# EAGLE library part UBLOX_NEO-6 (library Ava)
UBLOX NEO-6 GPS MODULE Author Anthony Stirk / http://ava.upuaut.net http://www.u-blox.com/images/downloads/Product_Docs/LEA-6_NEO-6_MAX_HardwareIntegrationManual_%28GPS.G6-HW-09007%29.pdf http://www.u-blox.com/images/downloads/Product_Docs/NEO-6_DataSheet_%28GPS.G6-HW-09005%29.pdf

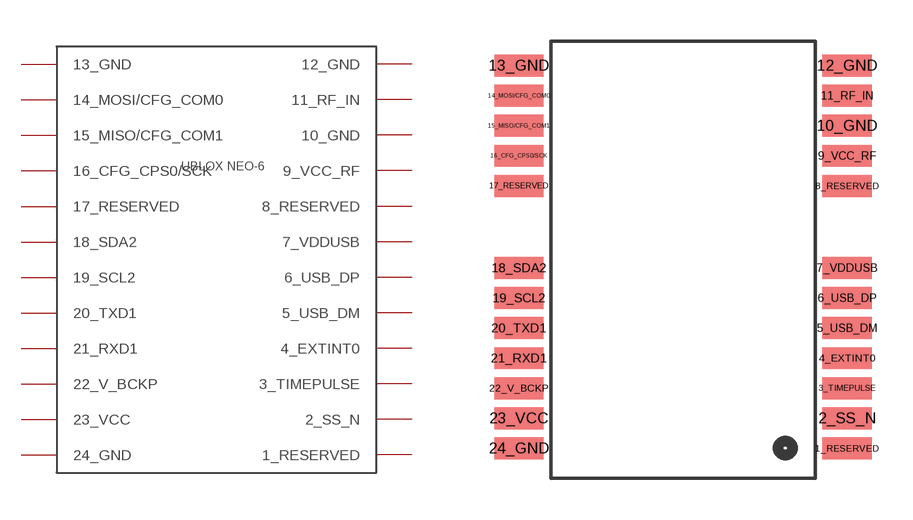
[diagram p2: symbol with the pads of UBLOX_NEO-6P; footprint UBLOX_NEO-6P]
Designator prefix -

## UBLOX_NEO-6  [UBLOX_NEO-6P]
1_RESERVED  1_RESERVED
2_SS_N  2_SS_N
3_TIMEPULSE  3_TIMEPULSE
4_EXTINT0  4_EXTINT0
5_USB_DM  5_USB_DM
6_USB_DP  6_USB_DP
7_VDDUSB  7_VDDUSB
8_RESERVED  8_RESERVED
9_VCC_RF  9_VCC_RF
10_GND  10_GND
11_RF_IN  11_RF_IN
12_GND  12_GND
13_GND  13_GND
14_MOSI/CFG_COM0  14_MOSI/CFG_COM0
15_MISO/CFG_COM1  15_MISO/CFG_COM1
16_CFG_CPS0/SCK  16_CFG_CPS0/SCK
17_RESERVED  17_RESERVED
18_SDA2  18_SDA2
19_SCL2  19_SCL2
20_TXD1  20_TXD1
21_RXD1  21_RXD1
22_V_BCKP  22_V_BCKP
23_VCC  23_VCC
24_GND  24_GND

## Footprint UBLOX_NEO-6P (pad centres in mm)
NEO-6 Series - u-blox 6 NEO Series GALILEO-Ready GPS Modules The NEO-6 module series brings the high performance, 50-channel u-blox 6 positioning engine, to the miniature NEO form factor. The u-blox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
smd 1.8 x 0.8: 1_RESERVED 6.4,-7.4; 2_SS_N 6.4,-6.3; 3_TIMEPULSE 6.4,-5.2; 4_EXTINT0 6.4,-4.1; 5_USB_DM 6.4,-3; 6_USB_DP 6.4,-1.9; 7_VDDUSB 6.4,-0.8; 8_RESERVED 6.4,2.2; 9_VCC_RF 6.4,3.3; 10_GND 6.4,4.4; 11_RF_IN 6.4,5.5; 12_GND 6.4,6.6; 13_GND -5.6,6.6; 14_MOSI/CFG_COM0 -5.6,5.5; 15_MISO/CFG_COM1 -5.6,4.4; 16_CFG_CPS0/SCK -5.6,3.3; 17_RESERVED -5.6,2.2; 18_SDA2 -5.6,-0.8; 19_SCL2 -5.6,-1.9; 20_TXD1 -5.6,-3; 21_RXD1 -5.6,-4.1; 22_V_BCKP -5.6,-5.2; 23_VCC -5.6,-6.3; 24_GND -5.6,-7.4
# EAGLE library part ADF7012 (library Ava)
ADF7012 Multichannel ISM Band FSK/GFSK/OOK/GOOK/ASK Transmitter http://www.analog.com/static/imported-files/data_sheets/ADF7012.pdf

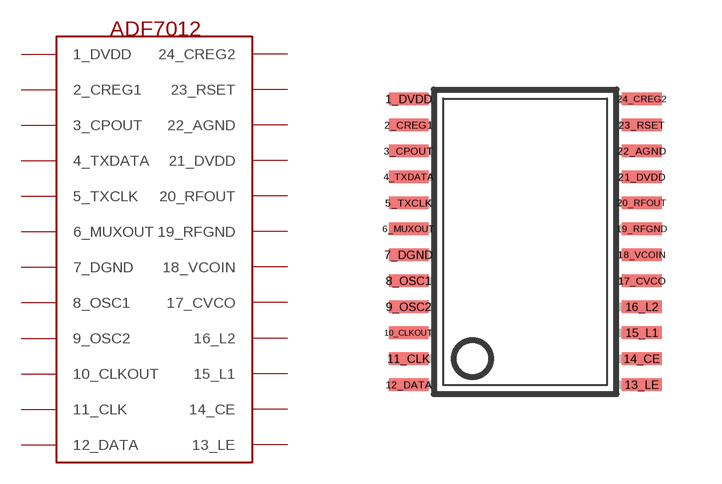
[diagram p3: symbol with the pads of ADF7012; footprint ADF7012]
Designator prefix -

## ADF7012  [ADF7012]
1_DVDD  1_DVDD
2_CREG1  2_CREG1
3_CPOUT  3_CPOUT
4_TXDATA  4_TXDATA
5_TXCLK  5_TXCLK
6_MUXOUT  6_MUXOUT
7_DGND  7_DGND
8_OSC1  8_OSC1
9_OSC2  9_OSC2
10_CLKOUT  10_CLKOUT
11_CLK  11_CLK
12_DATA  12_DATA
13_LE  13_LE
14_CE  14_CE
15_L1  15_L1
16_L2  16_L2
17_CVCO  17_CVCO
18_VCOIN  18_VCOIN
19_RFGND  19_RFGND
20_RFOUT  20_RFOUT
21_DVDD  21_DVDD
22_AGND  22_AGND
23_RSET  23_RSET
24_CREG2  24_CREG2

## Footprint ADF7012 (pad centres in mm)
ADF7012 Multichannel ISM Band FSK/GFSK/OOK/GOOK/ASK Transmitter http://www.analog.com/static/imported-files/data_sheets/ADF7012.pdf
smd 0.991 x 0.305: 1_DVDD -5.458,8.655; 2_CREG1 -5.458,8.005; 3_CPOUT -5.458,7.355; 4_TXDATA -5.458,6.705; 5_TXCLK -5.458,6.055; 6_MUXOUT -5.458,5.405; 7_DGND -5.458,4.755; 8_OSC1 -5.458,4.105; 9_OSC2 -5.458,3.455; 10_CLKOUT -5.458,2.805; 11_CLK -5.458,2.155; 12_DATA -5.458,1.505; 13_LE 0.378,1.505; 14_CE 0.378,2.155; 15_L1 0.378,2.805; 16_L2 0.378,3.455; 17_CVCO 0.378,4.105; 18_VCOIN 0.378,4.755; 19_RFGND 0.378,5.405; 20_RFOUT 0.378,6.055; 21_DVDD 0.378,6.705; 22_AGND 0.378,7.355; 23_RSET 0.378,8.005; 24_CREG2 0.378,8.655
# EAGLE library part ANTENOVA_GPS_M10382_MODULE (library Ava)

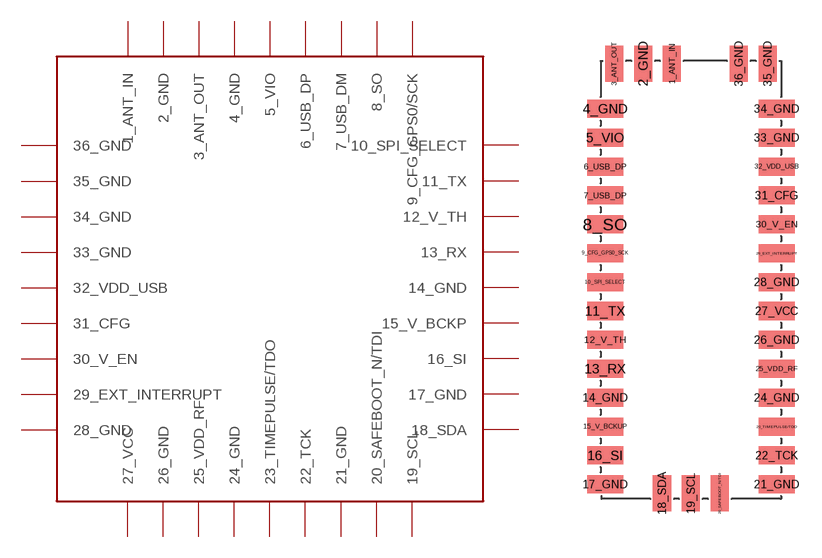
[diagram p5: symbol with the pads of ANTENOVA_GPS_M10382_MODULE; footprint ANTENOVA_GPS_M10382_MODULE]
Designator prefix -

## ANTENOVA_GPS_M10382_MODULE  [ANTENOVA_GPS_M10382_MODULE]
1_ANT_IN  1_ANT_IN
2_GND  2_GND
3_ANT_OUT  3_ANT_OUT
4_GND  4_GND
5_VIO  5_VIO
6_USB_DP  6_USB_DP
7_USB_DP  7_USB_DM
8_SO  8_SO
9_CFG_GPS0_SCK  9_CFG_GPS0/SCK
10_SPI_SELECT  10_SPI_SELECT
11_TX  11_TX
12_V_TH  12_V_TH
13_RX  13_RX
14_GND  14_GND
15_V_BCKUP  15_V_BCKP
16_SI  16_SI
17_GND  17_GND
18_SDA  18_SDA
19_SCL  19_SCL
20_SAFEBOOT_N/TDI  20_SAFEBOOT_N/TDI
21_GND  21_GND
22_TCK  22_TCK
23_TIMEPULSE/TDO  23_TIMEPULSE/TDO
24_GND  24_GND
25_VDD_RF  25_VDD_RF
26_GND  26_GND
27_VCC  27_VCC
28_GND  28_GND
29_EXT_INTERRUPT  29_EXT_INTERRUPT
30_V_EN  30_V_EN
31_CFG  31_CFG
32_VDD_USB  32_VDD_USB
33_GND  33_GND
34_GND  34_GND
35_GND  35_GND
36_GND  36_GND

## Footprint ANTENOVA_GPS_M10382_MODULE (pad centres in mm)
GPS RADIONOVA M10382 RF Antenna Module (SMD) Low profile SMD mount u-blox 6 based GPS radio antenna module suitable for L1-band and A-GPS systems. Dimensions: 24.2 x 9.9 x 3.9mm Frequency: 1575 MHz
smd 1 x 2: 1_ANT_IN -1.38,12.43; 2_GND -2.98,12.43; 3_ANT_OUT -4.58,12.43; 18_SDA -1.93,-11.37; 19_SCL -0.33,-11.37; 20_SAFEBOOT_N/TDI 1.27,-11.37; 35_GND 3.92,12.43; 36_GND 2.32,12.43
smd 2 x 1: 4_GND -5.08,9.93; 5_VIO -5.08,8.33; 6_USB_DP -5.08,6.73; 7_USB_DP -5.08,5.13; 8_SO -5.08,3.53; 9_CFG_GPS0_SCK -5.08,1.93; 10_SPI_SELECT -5.08,0.33; 11_TX -5.08,-1.27; 12_V_TH -5.08,-2.87; 13_RX -5.08,-4.47; 14_GND -5.08,-6.07; 15_V_BCKUP -5.08,-7.67; 16_SI -5.08,-9.27; 17_GND -5.08,-10.87; 21_GND 4.42,-10.87; 22_TCK 4.42,-9.27; 23_TIMEPULSE/TDO 4.42,-7.67; 24_GND 4.42,-6.07; 25_VDD_RF 4.42,-4.47; 26_GND 4.42,-2.87; 27_VCC 4.42,-1.27; 28_GND 4.42,0.33; 29_EXT_INTERRUPT 4.42,1.93; 30_V_EN 4.42,3.53; 31_CFG 4.42,5.13; 32_VDD_USB 4.42,6.73; 33_GND 4.42,8.33; 34_GND 4.42,9.93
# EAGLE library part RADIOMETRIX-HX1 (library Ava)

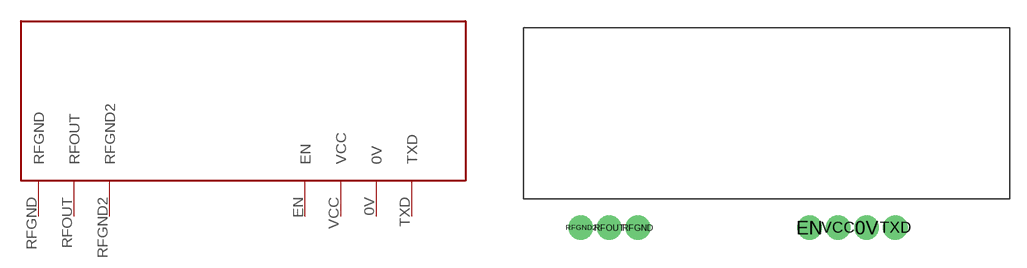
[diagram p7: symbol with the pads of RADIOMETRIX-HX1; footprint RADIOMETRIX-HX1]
Designator prefix -

## RADIOMETRIX-HX1  [RADIOMETRIX-HX1]
0V  0V
EN  EN
RFGND  RFGND
RFGND2  RFGND2
RFOUT  RFOUT
TXD  TXD
VCC  VCC

## Footprint RADIOMETRIX-HX1 (pad centres in mm)
drill 0.7 pad 2.184: 0V 8.89,-10.16; EN 3.81,-10.16; RFGND -11.43,-10.16; RFGND2 -16.51,-10.16; RFOUT -13.97,-10.16; TXD 11.43,-10.16; VCC 6.35,-10.16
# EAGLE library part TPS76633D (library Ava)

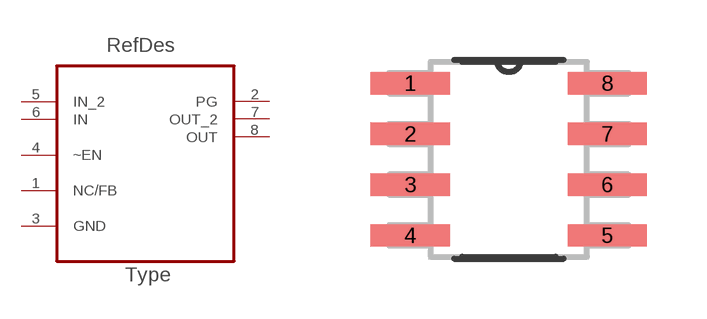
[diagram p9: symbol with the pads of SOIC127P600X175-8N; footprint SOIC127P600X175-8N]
Designator prefix U

## TPS76633D (DESCRIPTION: ULTRALOW QUIESCENT CURRENT 250-mA LOW DROPOUT VOLTAGE REGULATORS; MPN: TPS76633D; OC_FARNELL: 8461422; OC_NEWARK: 77C1060; PACKAGE: SOIC-8; SUPPLIER: Texas Instruments)  [SOIC127P600X175-8N]
1  NC/FB  nc
2  PG  out
3  GND  pas
4  ~EN  in
5  IN_2  in
6  IN  in
7  OUT_2  out
8  OUT  out

## Footprint SOIC127P600X175-8N (pad centres in mm)
smd 1.981 x 0.559: 1 -2.464,1.905; 2 -2.464,0.635; 3 -2.464,-0.635; 4 -2.464,-1.905; 5 2.464,-1.905; 6 2.464,-0.635; 7 2.464,0.635; 8 2.464,1.905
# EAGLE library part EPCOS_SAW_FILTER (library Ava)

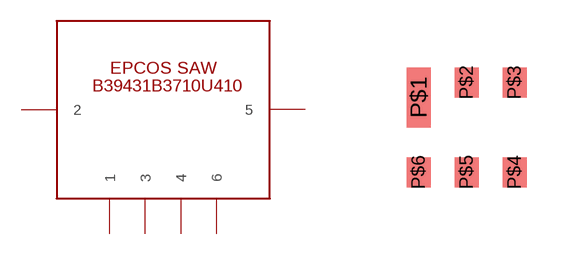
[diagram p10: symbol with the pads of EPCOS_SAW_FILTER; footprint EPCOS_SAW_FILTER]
Designator prefix -

## EPCOS_SAW_FILTER  [EPCOS_SAW_FILTER]
P$1  1
P$2  2
P$3  3
P$4  4
P$5  5
P$6  6

## Footprint EPCOS_SAW_FILTER (pad centres in mm)
smd 0.6 x 1.5: P$1 -1.2,0.75
smd 0.6 x 0.75: P$2 0,1.125; P$3 1.2,1.125; P$4 1.2,-1.125; P$5 0,-1.125; P$6 -1.2,-1.125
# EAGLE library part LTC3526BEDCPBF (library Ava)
Low Dropout Linear Regulators

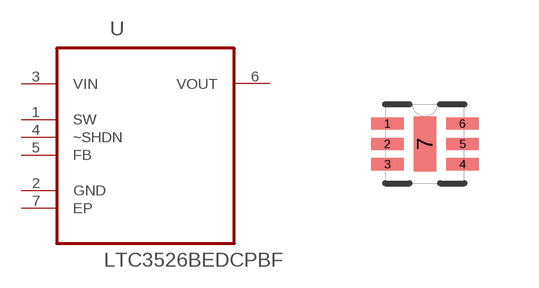
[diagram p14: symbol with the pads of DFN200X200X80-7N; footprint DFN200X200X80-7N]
Designator prefix U

## LTC3526BEDCPBF (MPN: LTC3526BEDC#PBF; OC_FARNELL: 1858699; OC_NEWARK: 61R9521; PACKAGE: DFN-6; SUPPLIER: Linear Technology)  [DFN200X200X80-7N]
1  SW  pas
2  GND  pas
3  VIN  pwr
4  ~SHDN  in
5  FB  in
6  VOUT  out
7  EP  pas

## Footprint DFN200X200X80-7N (pad centres in mm)
smd 0.813 x 0.305: 1 -0.94,0.508; 2 -0.94,0; 3 -0.94,-0.508; 4 0.94,-0.508; 5 0.94,0; 6 0.94,0.508
smd 0.559 x 1.372: 7 0,0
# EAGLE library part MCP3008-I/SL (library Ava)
10BIT ADC, 8 CH, SPI, SMD

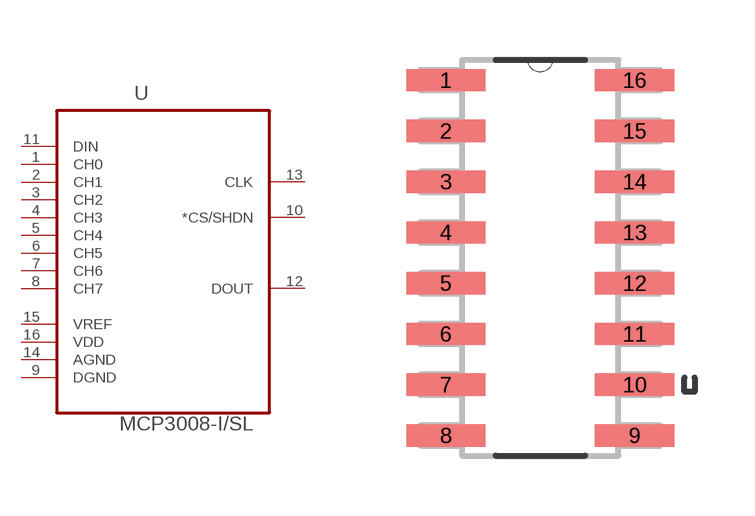
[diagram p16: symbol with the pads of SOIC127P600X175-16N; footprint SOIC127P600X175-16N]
Designator prefix U

## MCP3008-I/SL (MPN: MCP3008-I/SL; OC_FARNELL: 1292241; OC_NEWARK: 19C7201; PACKAGE: SOIC16; SUPPLIER: Microchip)  [SOIC127P600X175-16N]
1  CH0  in
2  CH1  in
3  CH2  in
4  CH3  in
5  CH4  in
6  CH5  in
7  CH6  in
8  CH7  in
9  DGND  pas
10  *CS/SHDN  in
11  DIN  in
12  DOUT  out
13  CLK  in
14  AGND  pas
15  VREF  in
16  VDD  pwr

## Footprint SOIC127P600X175-16N (pad centres in mm)
smd 1.981 x 0.559: 1 -2.362,4.445; 2 -2.362,3.175; 3 -2.362,1.905; 4 -2.362,0.635; 5 -2.362,-0.635; 6 -2.362,-1.905; 7 -2.362,-3.175; 8 -2.362,-4.445; 9 2.362,-4.445; 10 2.362,-3.175; 11 2.362,-1.905; 12 2.362,-0.635; 13 2.362,0.635; 14 2.362,1.905; 15 2.362,3.175; 16 2.362,4.445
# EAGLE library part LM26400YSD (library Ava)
Wide Input Range Buck Regulator

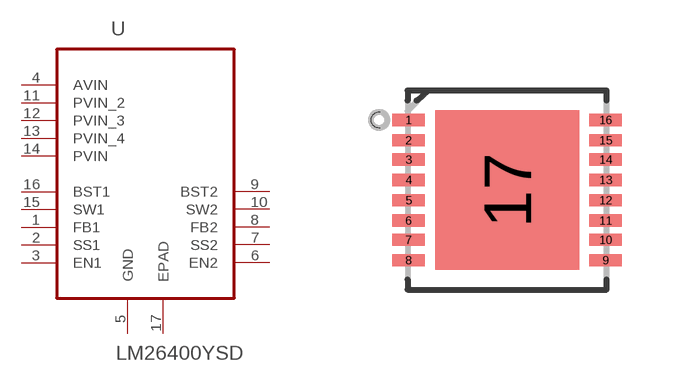
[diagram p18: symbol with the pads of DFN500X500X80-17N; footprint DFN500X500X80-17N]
Designator prefix U

## LM26400YSD (MPN: LM26400YSD; OC_FARNELL: 1333957; OC_NEWARK: 34M6729; PACKAGE: DFN-16; SUPPLIER: National Semiconductors)  [DFN500X500X80-17N]
1  FB1  in
2  SS1  in
3  EN1  in
4  AVIN  pwr
5  GND  pas
6  EN2  in
7  SS2  in
8  FB2  in
9  BST2  in
10  SW2  out
11  PVIN_2  pwr
12  PVIN_3  pwr
13  PVIN_4  pwr
14  PVIN  pwr
15  SW1  out
16  BST1  in
17  EPAD  pas

## Footprint DFN500X500X80-17N (pad centres in mm)
smd 0.813 x 0.305: 1 -2.464,1.753; 2 -2.464,1.245; 3 -2.464,0.762; 4 -2.464,0.254; 5 -2.464,-0.254; 6 -2.464,-0.762; 7 -2.464,-1.245; 8 -2.464,-1.753; 9 2.464,-1.753; 10 2.464,-1.245; 11 2.464,-0.762; 12 2.464,-0.254; 13 2.464,0.254; 14 2.464,0.762; 15 2.464,1.245; 16 2.464,1.753
smd 3.607 x 3.988: 17 0,0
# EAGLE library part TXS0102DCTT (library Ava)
BIDIRECTIONAL VOLTAGE-LEVEL TRANSLATOR

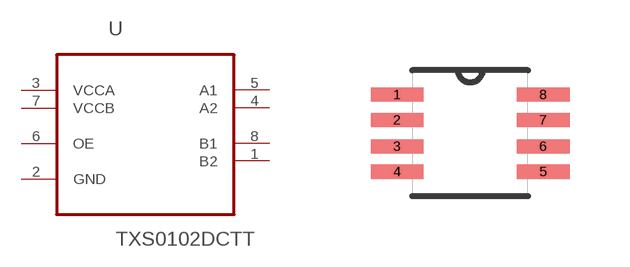
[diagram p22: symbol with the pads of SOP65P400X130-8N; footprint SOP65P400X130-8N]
Designator prefix U

## TXS0102DCTT (MPN: TXS0102DCTT; OC_FARNELL: 1567203; OC_NEWARK: 48M1002; PACKAGE: SSOP-8; SUPPLIER: Texas Instruments)  [SOP65P400X130-8N]
1  B2
2  GND  pas
3  VCCA  pwr
4  A2
5  A1
6  OE  in
7  VCCB  pwr
8  B1

## Footprint SOP65P400X130-8N (pad centres in mm)
smd 1.321 x 0.356: 1 -1.829,0.965; 2 -1.829,0.33; 3 -1.829,-0.33; 4 -1.829,-0.965; 5 1.829,-0.965; 6 1.829,-0.33; 7 1.829,0.33; 8 1.829,0.965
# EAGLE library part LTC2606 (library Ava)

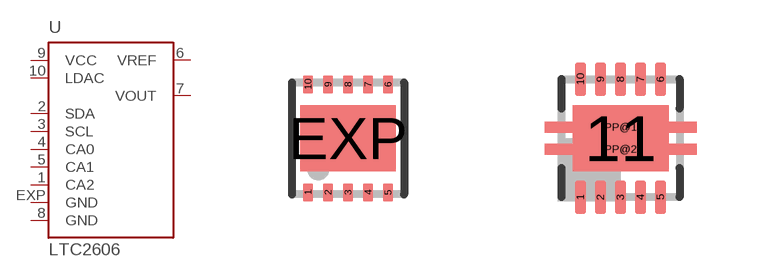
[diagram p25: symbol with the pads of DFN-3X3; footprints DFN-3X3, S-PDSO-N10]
Designator prefix -

## LTC2606  [DFN-3X3]
1  CA2  in
2  SDA  in
3  SCL  out
4  CA0  in
5  CA1  in
6  VREF  in
7  VOUT  in
8  GND  pwr
9  VCC  pwr
10  LDAC  in
EXP  GND  pwr

## LTC2606LARGERPADS  [S-PDSO-N10]
1  CA2  in
2  SDA  in
3  SCL  out
4  CA0  in
5  CA1  in
6  VREF  in
7  VOUT  in
8  GND  pwr
9  VCC  pwr
10  LDAC  in
11  GND  pwr
PP@1  GND  pwr
PP@2  GND  pwr

## Footprint DFN-3X3 (pad centres in mm)
smd 0.25 x 0.45: 1 -1,-1.35; 2 -0.5,-1.35; 3 0,-1.35; 4 0.5,-1.35; 5 1,-1.35; 6 1,1.35; 7 0.5,1.35; 8 0,1.35; 9 -0.5,1.35; 10 -1,1.35
smd 2.38 x 1.65: EXP 0,0

## Footprint S-PDSO-N10 (pad centres in mm)
smd 0.28 x 0.85: 1 -1,-1.475; 2 -0.5,-1.475; 3 0,-1.475; 4 0.5,-1.475; 5 1,-1.475; 6 1,1.475; 7 0.5,1.475; 8 0,1.475; 9 -0.5,1.475; 10 -1,1.475
smd 2.4 x 1.65: 11 0,0
smd 3.8 x 0.28: PP@1 0,0.275; PP@2 0,-0.275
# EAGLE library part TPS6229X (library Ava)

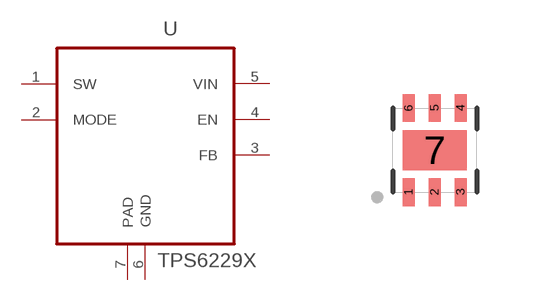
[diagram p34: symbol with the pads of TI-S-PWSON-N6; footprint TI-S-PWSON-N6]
Designator prefix -

## TPS6229X  [TI-S-PWSON-N6]
1  SW  pwr
2  MODE  pas
3  FB  in
4  EN  in
5  VIN  out
6  GND  pas
7  PAD  pas

## Footprint TI-S-PWSON-N6 (pad centres in mm)
smd 0.3 x 0.7: 1 -0.65,-1.05; 2 0,-1.05; 3 0.65,-1.05; 4 0.65,1.05; 5 0,1.05; 6 -0.65,1.05
smd 1.6 x 1: 7 0,0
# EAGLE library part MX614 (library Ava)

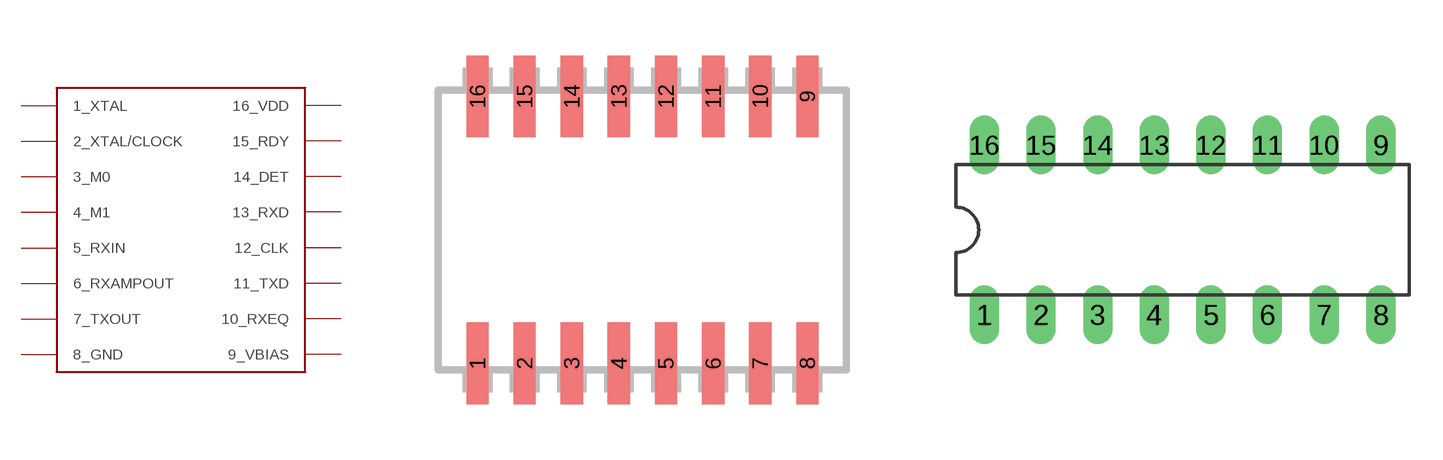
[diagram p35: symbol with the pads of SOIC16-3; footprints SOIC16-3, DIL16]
Designator prefix -

## MX614  [SOIC16-3]
1  1_XTAL  pwr
2  2_XTAL/CLOCK
3  3_M0
4  4_M1
5  5_RXIN
6  6_RXAMPOUT
7  7_TXOUT  pwr
8  8_GND  pwr
9  9_VBIAS  pwr
10  10_RXEQ  pwr
11  11_TXD
12  12_CLK  pwr
13  13_RXD
14  14_DET
15  15_RDY
16  16_VDD

## MX614DIL16  [DIL16]
Pads as for SOIC16-3

## Footprint SOIC16-3 (pad centres in mm)
smd 0.6 x 2.2: 1 -4.445,-3.6; 2 -3.175,-3.6; 3 -1.905,-3.6; 4 -0.635,-3.6; 5 0.635,-3.6; 6 1.905,-3.6; 7 3.175,-3.6; 8 4.445,-3.6; 9 4.445,3.6; 10 3.175,3.6; 11 1.905,3.6; 12 0.635,3.6; 13 -0.635,3.6; 14 -1.905,3.6; 15 -3.175,3.6; 16 -4.445,3.6

## Footprint DIL16 (pad centres in mm)
drill 0.813 long: 1 -8.89,-3.81; 2 -6.35,-3.81; 3 -3.81,-3.81; 4 -1.27,-3.81; 5 1.27,-3.81; 6 3.81,-3.81; 7 6.35,-3.81; 8 8.89,-3.81; 9 8.89,3.81; 10 6.35,3.81; 11 3.81,3.81; 12 1.27,3.81; 13 -1.27,3.81; 14 -3.81,3.81; 15 -6.35,3.81; 16 -8.89,3.81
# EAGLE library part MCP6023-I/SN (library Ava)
IC OPAMP 2.5V R-R I/O

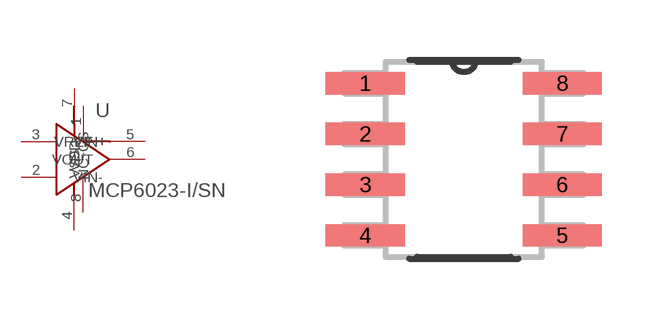
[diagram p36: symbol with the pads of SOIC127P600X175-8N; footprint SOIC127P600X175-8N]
Designator prefix U

## MCP6023-I/SN (MPN: MCP6023-I/SN; OC_FARNELL: 1629353; OC_NEWARK: 92C2412; PACKAGE: 8 SOIC; SUPPLIER: Microchip)  [SOIC127P600X175-8N]
1  NC  nc
2  VIN-  in
3  VIN+  in
4  VSS  pas
5  VREF  out
6  VOUT  out
7  VDD  pwr
8  ~CS  out

## Footprint SOIC127P600X175-8N (pad centres in mm)
smd 1.981 x 0.559: 1 -2.464,1.905; 2 -2.464,0.635; 3 -2.464,-0.635; 4 -2.464,-1.905; 5 2.464,-1.905; 6 2.464,-0.635; 7 2.464,0.635; 8 2.464,1.905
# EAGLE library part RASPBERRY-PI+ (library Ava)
Samtec SSW-120-01-T-D

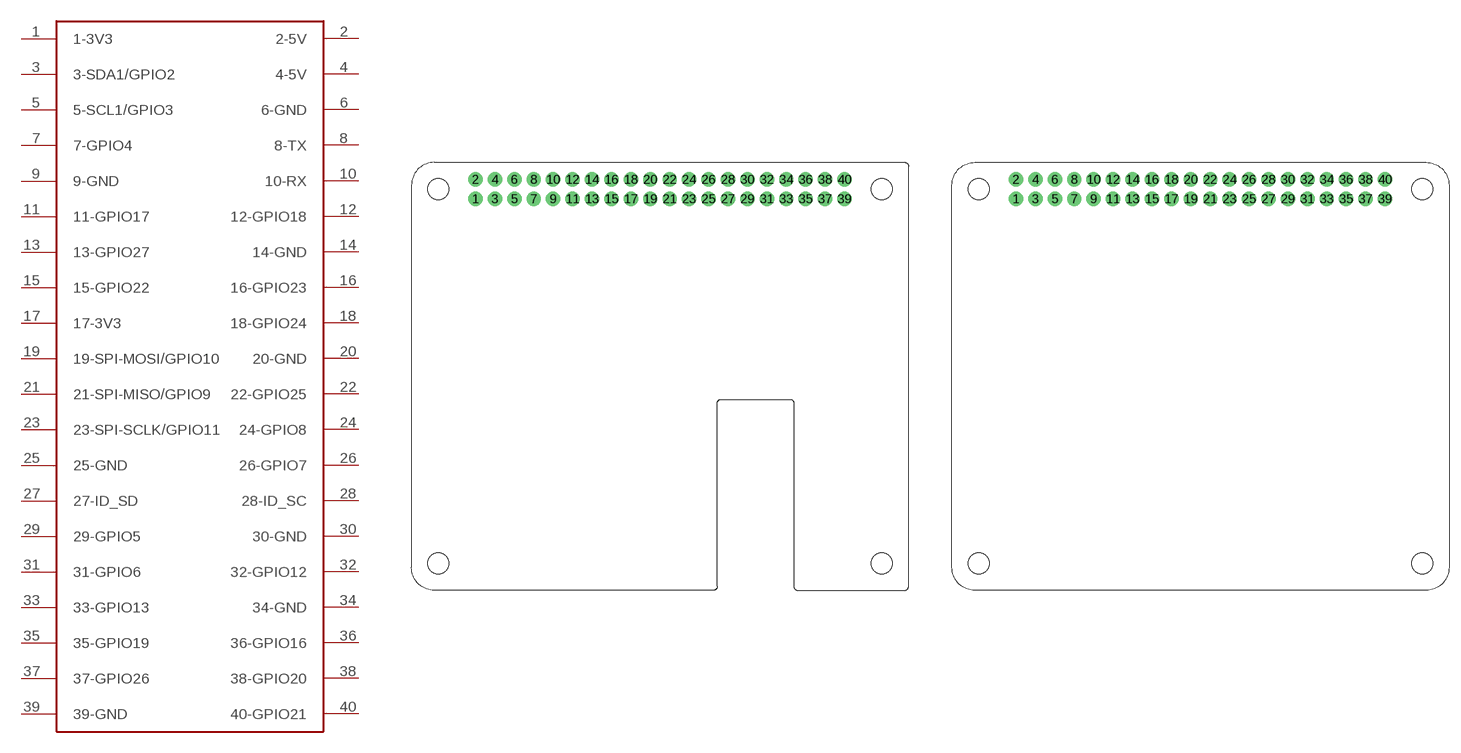
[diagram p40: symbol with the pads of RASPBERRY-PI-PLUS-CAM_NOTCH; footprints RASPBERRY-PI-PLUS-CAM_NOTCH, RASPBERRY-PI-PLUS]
Designator prefix -

## RASPBERRY-PI+  [RASPBERRY-PI-PLUS-CAM_NOTCH]
1  1-3V3
2  2-5V
3  3-SDA1/GPIO2
4  4-5V
5  5-SCL1/GPIO3
6  6-GND
7  7-GPIO4
8  8-TX
9  9-GND
10  10-RX
11  11-GPIO17
12  12-GPIO18
13  13-GPIO27
14  14-GND
15  15-GPIO22
16  16-GPIO23
17  17-3V3
18  18-GPIO24
19  19-SPI-MOSI/GPIO10
20  20-GND
21  21-SPI-MISO/GPIO9
22  22-GPIO25
23  23-SPI-SCLK/GPIO11
24  24-GPIO8
25  25-GND
26  26-GPIO7
27  27-ID_SD
28  28-ID_SC
29  29-GPIO5
30  30-GND
31  31-GPIO6
32  32-GPIO12
33  33-GPIO13
34  34-GND
35  35-GPIO19
36  36-GPIO16
37  37-GPIO26
38  38-GPIO20
39  39-GND
40  40-GPIO21

## RASPBERRY-PI+NONOTCHES  [RASPBERRY-PI-PLUS]
Pads as for RASPBERRY-PI-PLUS-CAM_NOTCH

## RASPBERRY-PI+CAM/DISPLAY_NOTCH  [RASPBERRY-PI-PLUS-DISPLAY/CAM_NOTCH]
Pads as for RASPBERRY-PI-PLUS-CAM_NOTCH

## RASPBERRY-PI+RASPBERRY-PI-PLUS-NOOUTLINE  [RASPBERRY-PI-PLUS-NOOUTLINE]
Pads as for RASPBERRY-PI-PLUS-CAM_NOTCH

## Footprint RASPBERRY-PI-PLUS-CAM_NOTCH (pad centres in mm)
drill 1.016 pad 1.88: 1 -34.13,23.23; 2 -34.13,25.77; 3 -31.59,23.23; 4 -31.59,25.77; 5 -29.05,23.23; 6 -29.05,25.77; 7 -26.51,23.23; 8 -26.51,25.77; 9 -23.97,23.23; 10 -23.97,25.77; 11 -21.43,23.23; 12 -21.43,25.77; 13 -18.89,23.23; 14 -18.89,25.77; 15 -16.35,23.23; 16 -16.35,25.77; 17 -13.81,23.23; 18 -13.81,25.77; 19 -11.27,23.23; 20 -11.27,25.77; 21 -8.73,23.23; 22 -8.73,25.77; 23 -6.19,23.23; 24 -6.19,25.77; 25 -3.65,23.23; 26 -3.65,25.77; 27 -1.11,23.23; 28 -1.11,25.77; 29 1.43,23.23; 30 1.43,25.77; 31 3.97,23.23; 32 3.98,25.77; 33 6.51,23.23; 34 6.51,25.77; 35 9.05,23.23; 36 9.05,25.77; 37 11.59,23.23; 38 11.59,25.77; 39 14.13,23.23; 40 14.13,25.77
hole 2.75 at -39,24.5
hole 2.75 at 19,24.5
hole 2.75 at -39,-24.5
hole 2.75 at 19,-24.5

## Footprint RASPBERRY-PI-PLUS (pad centres in mm)
drill 1.016 pad 1.88: 1 -34.13,23.23; 2 -34.13,25.77; 3 -31.59,23.23; 4 -31.59,25.77; 5 -29.05,23.23; 6 -29.05,25.77; 7 -26.51,23.23; 8 -26.51,25.77; 9 -23.97,23.23; 10 -23.97,25.77; 11 -21.43,23.23; 12 -21.43,25.77; 13 -18.89,23.23; 14 -18.89,25.77; 15 -16.35,23.23; 16 -16.35,25.77; 17 -13.81,23.23; 18 -13.81,25.77; 19 -11.27,23.23; 20 -11.27,25.77; 21 -8.73,23.23; 22 -8.73,25.77; 23 -6.19,23.23; 24 -6.19,25.77; 25 -3.65,23.23; 26 -3.65,25.77; 27 -1.11,23.23; 28 -1.11,25.77; 29 1.43,23.23; 30 1.43,25.77; 31 3.97,23.23; 32 3.98,25.77; 33 6.51,23.23; 34 6.51,25.77; 35 9.05,23.23; 36 9.05,25.77; 37 11.59,23.23; 38 11.59,25.77; 39 14.13,23.23; 40 14.13,25.77
hole 2.75 at -39,24.5
hole 2.75 at 19,24.5
hole 2.75 at -39,-24.5
hole 2.75 at 19,-24.5

## Footprint RASPBERRY-PI-PLUS-DISPLAY/CAM_NOTCH (pad centres in mm)
drill 1.016 pad 1.88: 1 -34.13,23.23; 2 -34.13,25.77; 3 -31.59,23.23; 4 -31.59,25.77; 5 -29.05,23.23; 6 -29.05,25.77; 7 -26.51,23.23; 8 -26.51,25.77; 9 -23.97,23.23; 10 -23.97,25.77; 11 -21.43,23.23; 12 -21.43,25.77; 13 -18.89,23.23; 14 -18.89,25.77; 15 -16.35,23.23; 16 -16.35,25.77; 17 -13.81,23.23; 18 -13.81,25.77; 19 -11.27,23.23; 20 -11.27,25.77; 21 -8.73,23.23; 22 -8.73,25.77; 23 -6.19,23.23; 24 -6.19,25.77; 25 -3.65,23.23; 26 -3.65,25.77; 27 -1.11,23.23; 28 -1.11,25.77; 29 1.43,23.23; 30 1.43,25.77; 31 3.97,23.23; 32 3.98,25.77; 33 6.51,23.23; 34 6.51,25.77; 35 9.05,23.23; 36 9.05,25.77; 37 11.59,23.23; 38 11.59,25.77; 39 14.13,23.23; 40 14.13,25.77
hole 2.75 at -39,24.5
hole 2.75 at 19,24.5
hole 2.75 at -39,-24.5
hole 2.75 at 19,-24.5

## Footprint RASPBERRY-PI-PLUS-NOOUTLINE (pad centres in mm)
drill 1.016 pad 1.88: 1 -23.97,24.5; 2 -23.97,27.04; 3 -21.43,24.5; 4 -21.43,27.04; 5 -18.89,24.5; 6 -18.89,27.04; 7 -16.35,24.5; 8 -16.35,27.04; 9 -13.81,24.5; 10 -13.81,27.04; 11 -11.27,24.5; 12 -11.27,27.04; 13 -8.73,24.5; 14 -8.73,27.04; 15 -6.19,24.5; 16 -6.19,27.04; 17 -3.65,24.5; 18 -3.65,27.04; 19 -1.11,24.5; 20 -1.11,27.04; 21 1.43,24.5; 22 1.43,27.04; 23 3.97,24.5; 24 3.97,27.04; 25 6.51,24.5; 26 6.51,27.04; 27 9.05,24.5; 28 9.05,27.04; 29 11.59,24.5; 30 11.59,27.04; 31 14.13,24.5; 32 14.14,27.04; 33 16.67,24.5; 34 16.67,27.04; 35 19.21,24.5; 36 19.21,27.04; 37 21.75,24.5; 38 21.75,27.04; 39 24.29,24.5; 40 24.29,27.04
hole 2.75 at -28.84,25.77
hole 2.75 at 29.16,25.77
hole 2.75 at -28.84,-23.23
hole 2.75 at 29.16,-23.23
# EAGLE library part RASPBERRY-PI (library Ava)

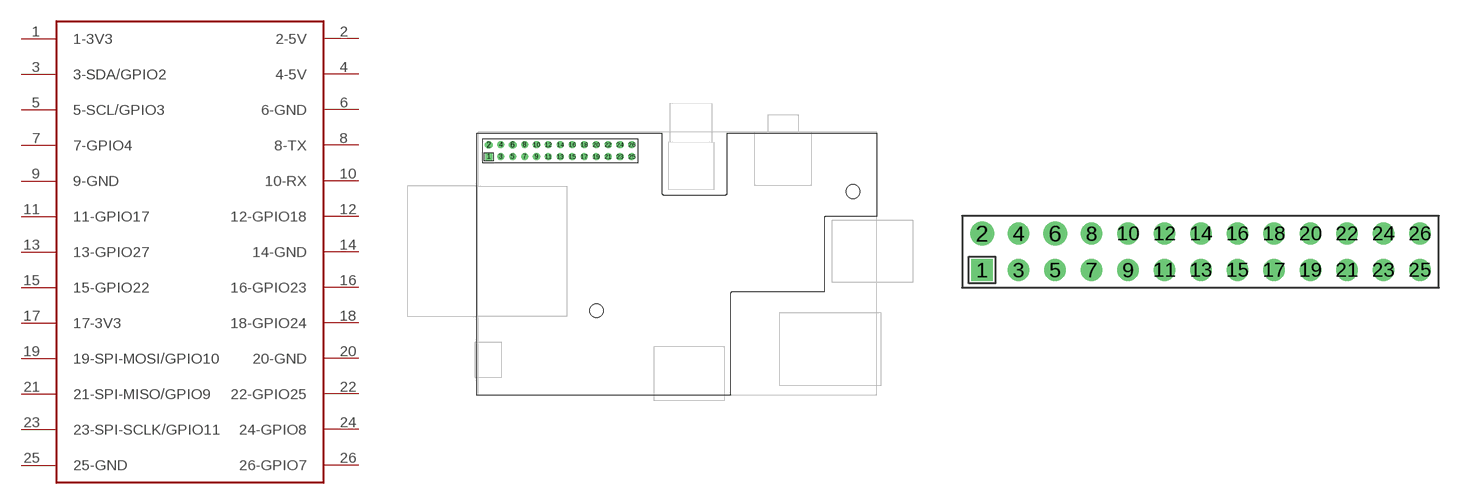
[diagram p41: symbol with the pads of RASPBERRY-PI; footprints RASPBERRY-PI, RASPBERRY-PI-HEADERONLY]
Designator prefix -

## RASPBERRY-PI  [RASPBERRY-PI]
1  1-3V3
2  2-5V
3  3-SDA/GPIO2
4  4-5V
5  5-SCL/GPIO3
6  6-GND
7  7-GPIO4
8  8-TX
9  9-GND
10  10-RX
11  11-GPIO17
12  12-GPIO18
13  13-GPIO27
14  14-GND
15  15-GPIO22
16  16-GPIO23
17  17-3V3
18  18-GPIO24
19  19-SPI-MOSI/GPIO10
20  20-GND
21  21-SPI-MISO/GPIO9
22  22-GPIO25
23  23-SPI-SCLK/GPIO11
24  24-GPIO8
25  25-GND
26  26-GPIO7

## RASPBERRY-PIHEADERONLY  [RASPBERRY-PI-HEADERONLY]
Pads as for RASPBERRY-PI

## Footprint RASPBERRY-PI (pad centres in mm)
drill 1 square: 1 0,0
drill 1 pad 1.676: 2 0,2.54; 6 5.08,2.54
drill 1: 3 2.54,0; 4 2.54,2.54; 5 5.08,0; 7 7.62,0; 8 7.62,2.54; 9 10.16,0; 10 10.16,2.54; 11 12.7,0; 12 12.7,2.54; 13 15.24,0; 14 15.24,2.54; 15 17.78,0; 16 17.78,2.54; 17 20.32,0; 18 20.32,2.54; 19 22.86,0; 20 22.86,2.54; 21 25.4,0; 22 25.4,2.54; 23 27.94,0; 24 27.94,2.54; 25 30.48,0; 26 30.48,2.54
hole 2.9 at 22.96,-32.8
hole 2.9 at 77.55,-7.42

## Footprint RASPBERRY-PI-HEADERONLY (pad centres in mm)
drill 1 square: 1 -15.24,-1.27
drill 1 pad 1.676: 2 -15.24,1.27; 6 -10.16,1.27
drill 1: 3 -12.7,-1.27; 4 -12.7,1.27; 5 -10.16,-1.27; 7 -7.62,-1.27; 8 -7.62,1.27; 9 -5.08,-1.27; 10 -5.08,1.27; 11 -2.54,-1.27; 12 -2.54,1.27; 13 0,-1.27; 14 0,1.27; 15 2.54,-1.27; 16 2.54,1.27; 17 5.08,-1.27; 18 5.08,1.27; 19 7.62,-1.27; 20 7.62,1.27; 21 10.16,-1.27; 22 10.16,1.27; 23 12.7,-1.27; 24 12.7,1.27; 25 15.24,-1.27; 26 15.24,1.27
